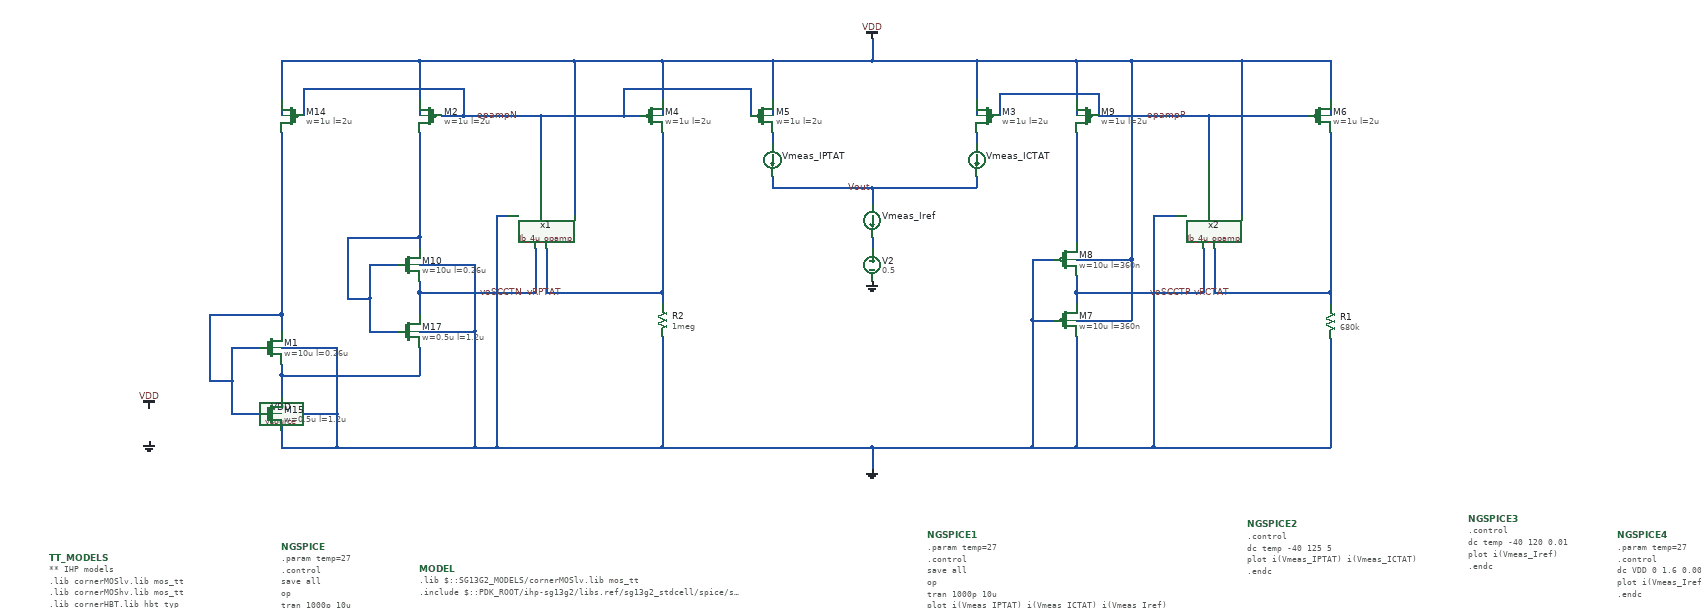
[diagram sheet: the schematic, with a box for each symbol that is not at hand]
v {xschem version=3.4.6 file_version=1.2}
G {}
K {}
V {}
S {}
E {}
N 1930 -970 1930 -930 {lab=opampP}
N 1810 -670 1850 -670 {lab=GND}
N 1810 -560 1850 -560 {lab=GND}
N 1890 -610 1890 -590 {lab=voSCCTP}
N 2130 -930 2130 -850 {lab=opampP}
N 1930 -930 2130 -930 {lab=opampP}
N 1340 -1030 1340 -930 {lab=VDD}
N 1710 -1030 1710 -930 {lab=VDD}
N 1890 -1030 1890 -930 {lab=VDD}
N 2350 -1030 2350 -930 {lab=VDD}
N 450 -1030 700 -1030 {lab=VDD}
N 1140 -1030 1140 -930 {lab=VDD}
N 1070 -930 1100 -930 {lab=opampN}
N 1070 -980 1070 -930 {lab=opampN}
N 1300 -980 1300 -930 {lab=opampN}
N 1750 -970 1750 -930 {lab=opampP}
N 700 -1030 700 -930 {lab=VDD}
N 920 -930 920 -850 {lab=opampN}
N 780 -930 920 -930 {lab=opampN}
N 980 -1030 1140 -1030 {lab=VDD}
N 700 -610 700 -570 {lab=voSCCTN}
N 700 -660 800 -660 {lab=GND}
N 800 -660 800 -540 {lab=GND}
N 700 -540 800 -540 {lab=GND}
N 610 -660 660 -660 {lab=#net1}
N 610 -600 610 -540 {lab=#net1}
N 610 -540 660 -540 {lab=#net1}
N 700 -710 700 -690 {lab=#net1}
N 570 -600 610 -600 {lab=#net1}
N 610 -660 610 -600 {lab=#net1}
N 570 -710 570 -600 {lab=#net1}
N 570 -710 700 -710 {lab=#net1}
N 700 -900 700 -710 {lab=#net1}
N 700 -610 910 -610 {lab=voSCCTN}
N 700 -630 700 -610 {lab=voSCCTN}
N 910 -690 910 -610 {lab=voSCCTN}
N 450 -460 450 -420 {lab=#net2}
N 450 -510 550 -510 {lab=GND}
N 550 -510 550 -390 {lab=GND}
N 450 -390 550 -390 {lab=GND}
N 360 -510 410 -510 {lab=#net3}
N 360 -450 360 -390 {lab=#net3}
N 360 -390 410 -390 {lab=#net3}
N 320 -450 360 -450 {lab=#net3}
N 360 -510 360 -450 {lab=#net3}
N 450 -460 700 -460 {lab=#net2}
N 450 -480 450 -460 {lab=#net2}
N 700 -510 700 -460 {lab=#net2}
N 450 -570 450 -540 {lab=#net3}
N 450 -1030 450 -930 {lab=VDD}
N 490 -980 490 -930 {lab=opampN}
N 490 -980 780 -980 {lab=opampN}
N 780 -980 780 -930 {lab=opampN}
N 740 -930 780 -930 {lab=opampN}
N 450 -370 450 -330 {lab=GND}
N 320 -570 320 -450 {lab=#net3}
N 320 -570 450 -570 {lab=#net3}
N 450 -900 450 -570 {lab=#net3}
N 1810 -670 1810 -560 {lab=GND}
N 2030 -330 2350 -330 {lab=GND}
N 800 -540 800 -330 {lab=GND}
N 550 -330 800 -330 {lab=GND}
N 550 -390 550 -330 {lab=GND}
N 450 -330 550 -330 {lab=GND}
N 1890 -560 1990 -560 {lab=VDD}
N 1140 -610 1140 -590 {lab=vRPTAT}
N 1140 -530 1140 -330 {lab=GND}
N 840 -330 1140 -330 {lab=GND}
N 930 -690 930 -610 {lab=vRPTAT}
N 930 -610 1140 -610 {lab=vRPTAT}
N 1140 -900 1140 -610 {lab=vRPTAT}
N 2140 -610 2350 -610 {lab=vRCTAT}
N 2350 -900 2350 -610 {lab=vRCTAT}
N 2140 -690 2140 -610 {lab=vRCTAT}
N 2120 -690 2120 -610 {lab=voSCCTP}
N 1890 -900 1890 -700 {lab=#net4}
N 1890 -530 1890 -330 {lab=GND}
N 1890 -610 2120 -610 {lab=voSCCTP}
N 1890 -640 1890 -610 {lab=voSCCTP}
N 1990 -670 1990 -560 {lab=VDD}
N 1890 -1030 1990 -1030 {lab=VDD}
N 2030 -750 2070 -750 {lab=GND}
N 2030 -750 2030 -330 {lab=GND}
N 1890 -330 2030 -330 {lab=GND}
N 2190 -1030 2350 -1030 {lab=VDD}
N 1810 -330 1890 -330 {lab=GND}
N 1810 -560 1810 -330 {lab=GND}
N 1520 -330 1810 -330 {lab=GND}
N 1750 -970 1930 -970 {lab=opampP}
N 1070 -980 1300 -980 {lab=opampN}
N 1140 -1030 1340 -1030 {lab=VDD}
N 1710 -1030 1890 -1030 {lab=VDD}
N 1520 -1030 1710 -1030 {lab=VDD}
N 1520 -1070 1520 -1030 {lab=VDD}
N 1340 -1030 1520 -1030 {lab=VDD}
N 1520 -330 1520 -290 {lab=GND}
N 1140 -330 1520 -330 {lab=GND}
N 840 -750 860 -750 {lab=GND}
N 840 -750 840 -330 {lab=GND}
N 800 -330 840 -330 {lab=GND}
N 1890 -670 1990 -670 {lab=VDD}
N 1990 -1030 1990 -670 {lab=VDD}
N 1520 -800 1710 -800 {lab=Vout}
N 1710 -820 1710 -800 {lab=Vout}
N 1340 -820 1340 -800 {lab=Vout}
N 1340 -900 1340 -880 {lab=#net5}
N 1710 -900 1710 -880 {lab=#net6}
N 1520 -800 1520 -770 {lab=Vout}
N 1340 -800 1520 -800 {lab=Vout}
N 1520 -710 1520 -690 {lab=#net7}
N 980 -1030 980 -750 {lab=VDD}
N 700 -1030 980 -1030 {lab=VDD}
N 2190 -1030 2190 -750 {lab=VDD}
N 1990 -1030 2190 -1030 {lab=VDD}
N 920 -930 1070 -930 {lab=opampN}
N 2130 -930 2310 -930 {lab=opampP}
N 2350 -610 2350 -587.5 {lab=vRCTAT}
N 2350 -527.5 2350 -330 {lab=GND}
C {code_shown.sym} 30 -130 0 0 {
name=TT_MODELS
only_toplevel=true
value="
** IHP models
.lib cornerMOSlv.lib mos_tt
.lib cornerMOShv.lib mos_tt
.lib cornerHBT.lib hbt_typ
.lib cornerRES.lib res_typ
"
spice_ignore=false
      }
C {vsource.sym} 210 -370 0 0 {name=VDD value=1 savecurrent=false}
C {vdd.sym} 210 -400 0 0 {name=l1 lab=VDD}
C {vdd.sym} 1520 -1070 0 0 {name=l2 lab=VDD}
C {gnd.sym} 210 -340 0 0 {name=l3 lab=GND}
C {devices/code_shown.sym} 450 -150 0 0 {name=NGSPICE only_toplevel=true
value="
.param temp=27
.control
save all
op
tran 1000p 10u
plot v(voSCCTP) v(vRPTAT) v(voSCCTN) v(vRCTAT) v(opampN) v(opampP) 
.endc
"


}
C {vsource.sym} 1520 -660 0 0 {name=V2 value=0.5 savecurrent=false}
C {gnd.sym} 1520 -630 0 0 {name=l6 lab=GND}
C {lab_pin.sym} 1520 -800 3 1 {name=p1 sig_type=std_logic lab=Vout}
C {devices/code_shown.sym} 700 -110 0 0 {name=MODEL
only_toplevel=true
format="tcleval( @value )"
value="
.lib $::SG13G2_MODELS/cornerMOSlv.lib mos_tt
.include $::PDK_ROOT/ihp-sg13g2/libs.ref/sg13g2_stdcell/spice/sg13g2_stdcell.spice
"
place=header}
C {sg13g2_pr/sg13_lv_pmos.sym} 1870 -560 0 0 {name=M7
l=360n
w=10u
ng=1
m=20
model=sg13_lv_pmos
spiceprefix=X
}
C {sg13g2_pr/sg13_lv_pmos.sym} 1870 -670 0 0 {name=M8
l=360n
w=10u
ng=1
m=1
model=sg13_lv_pmos
spiceprefix=X
}
C {sg13g2_pr/sg13_lv_nmos.sym} 680 -540 0 0 {name=M17
l=1.2u
w=0.5u
ng=1
m=1
model=sg13_lv_nmos
spiceprefix=X
}
C {sg13g2_pr/sg13_lv_pmos.sym} 470 -930 0 1 {name=M14
l=2u
w=1u
ng=1
m=1
model=sg13_lv_pmos
spiceprefix=X
}
C {sg13g2_pr/sg13_lv_nmos.sym} 430 -390 0 0 {name=M15
l=1.2u
w=0.5u
ng=1
m=1
model=sg13_lv_nmos
spiceprefix=X
}
C {gnd.sym} 1520 -290 0 0 {name=l4 lab=GND}
C {lab_pin.sym} 2100 -610 3 0 {name=p2 sig_type=std_logic lab=voSCCTP}
C {lab_pin.sym} 890 -610 3 0 {name=p3 sig_type=std_logic lab=voSCCTN}
C {/shared/designs/SSDOR_w_startup_1V_ihp/Ib_4u/Ib_4u_opamp/Ib_4u_opamp.sym} 860 -690 1 1 {name=x1}
C {/shared/designs/SSDOR_w_startup_1V_ihp/Ib_4u/Ib_4u_opamp/Ib_4u_opamp.sym} 2070 -690 1 1 {name=x2}
C {lab_pin.sym} 2170 -610 3 0 {name=p4 sig_type=std_logic lab=vRCTAT}
C {lab_pin.sym} 960 -610 3 0 {name=p5 sig_type=std_logic lab=vRPTAT}
C {ammeter.sym} 1340 -850 0 0 {name=Vmeas_IPTAT savecurrent=true spice_ignore=0}
C {devices/code_shown.sym} 1620 -170 0 0 {name=NGSPICE1 only_toplevel=true
value="
.param temp=27
.control
save all
op
tran 1000p 10u
plot i(Vmeas_IPTAT) i(Vmeas_ICTAT) i(Vmeas_Iref)
.endc
"


}
C {ammeter.sym} 1710 -850 0 0 {name=Vmeas_ICTAT savecurrent=true spice_ignore=0}
C {ammeter.sym} 1520 -740 0 0 {name=Vmeas_Iref savecurrent=true spice_ignore=0}
C {devices/code_shown.sym} 2200 -190 0 0 {name=NGSPICE2 only_toplevel=true
value="
.control 
dc temp -40 125 5
plot i(Vmeas_IPTAT) i(Vmeas_ICTAT)
.endc
"


}
C {devices/code_shown.sym} 2600 -200 0 0 {name=NGSPICE3 only_toplevel=true
value="
.control 
dc temp -40 120 0.01
plot i(Vmeas_Iref) 
.endc
"


}
C {sg13g2_pr/sg13_lv_pmos.sym} 720 -930 0 1 {name=M2
l=2u
w=1u
ng=1
m=1
model=sg13_lv_pmos
spiceprefix=X
}
C {sg13g2_pr/sg13_lv_pmos.sym} 1120 -930 0 0 {name=M4
l=2u
w=1u
ng=1
m=1
model=sg13_lv_pmos
spiceprefix=X
}
C {sg13g2_pr/sg13_lv_pmos.sym} 1320 -930 0 0 {name=M5
l=2u
w=1u
ng=1
m=4
model=sg13_lv_pmos
spiceprefix=X
}
C {sg13g2_pr/sg13_lv_pmos.sym} 1730 -930 0 1 {name=M3
l=2u
w=1u
ng=1
m=4
model=sg13_lv_pmos
spiceprefix=X
}
C {sg13g2_pr/sg13_lv_pmos.sym} 1910 -930 0 1 {name=M9
l=2u
w=1u
ng=1
m=1
model=sg13_lv_pmos
spiceprefix=X
}
C {sg13g2_pr/sg13_lv_pmos.sym} 2330 -930 0 0 {name=M6
l=2u
w=1u
ng=1
m=1
model=sg13_lv_pmos
spiceprefix=X
}
C {lab_pin.sym} 2090 -930 1 0 {name=p6 sig_type=std_logic lab=opampP}
C {lab_pin.sym} 880 -930 1 0 {name=p7 sig_type=std_logic lab=opampN}
C {res.sym} 1140 -560 0 0 {name=R2
value=1meg
footprint=1206
device=resistor
m=1}
C {res.sym} 2350 -557.5 0 0 {name=R1
value=680k
footprint=1206
device=resistor
m=1}
C {devices/code_shown.sym} 2870 -170 0 0 {name=NGSPICE4 only_toplevel=true
value="
.param temp=27
.control
dc VDD 0 1.6 0.0001
plot i(Vmeas_Iref)
.endc 
"


}
C {sg13g2_pr/sg13_lv_nmos.sym} 430 -510 0 0 {name=M1
l=0.26u
w=10u
ng=1
m=30
model=sg13_lv_nmos
spiceprefix=X
}
C {sg13g2_pr/sg13_lv_nmos.sym} 680 -660 0 0 {name=M10
l=0.26u
w=10u
ng=1
m=30
model=sg13_lv_nmos
spiceprefix=X
}
